VERSION 5.8 ;
BUSBITCHARS "[]" ;
DIVIDERCHAR "/" ;
UNITS
    DATABASE MICRONS 1000 ;
END UNITS

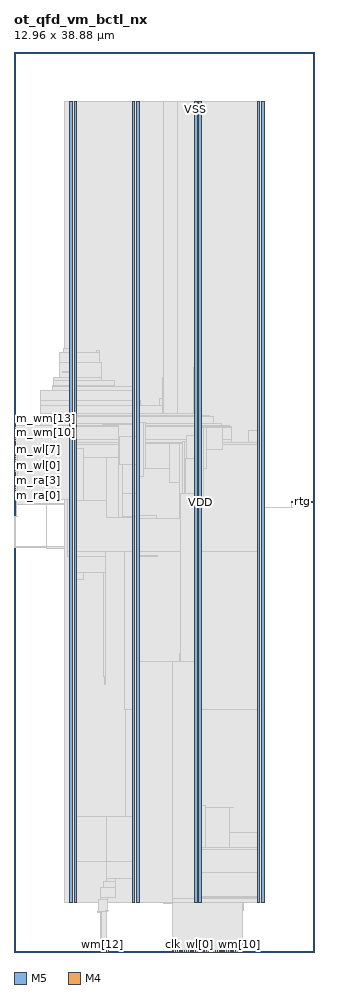
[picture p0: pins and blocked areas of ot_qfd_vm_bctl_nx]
MACRO ot_qfd_vm_bctl_nx
  FOREIGN ot_qfd_vm_bctl_nx 0 0 ;
  CLASS BLOCK ;
  SIZE 12.96 BY 38.88 ;
  PIN clk
    DIRECTION INPUT ;
    USE SIGNAL ;
    PORT
      LAYER M5 ;
        RECT  6.864 0 6.888 0.084 ;
    END
  END clk
  PIN m_ra[0]
    DIRECTION OUTPUT ;
    USE SIGNAL ;
    PORT
      LAYER M4 ;
        RECT  0 19.728 0.084 19.752 ;
    END
  END m_ra[0]
  PIN m_ra[1]
    DIRECTION OUTPUT ;
    USE SIGNAL ;
    PORT
      LAYER M4 ;
        RECT  0 19.824 0.084 19.848 ;
    END
  END m_ra[1]
  PIN m_ra[2]
    DIRECTION OUTPUT ;
    USE SIGNAL ;
    PORT
      LAYER M4 ;
        RECT  0 19.92 0.084 19.944 ;
    END
  END m_ra[2]
  PIN m_ra[3]
    DIRECTION OUTPUT ;
    USE SIGNAL ;
    PORT
      LAYER M4 ;
        RECT  0 20.016 0.084 20.04 ;
    END
  END m_ra[3]
  PIN m_ra[4]
    DIRECTION OUTPUT ;
    USE SIGNAL ;
    PORT
      LAYER M4 ;
        RECT  0 20.112 0.084 20.136 ;
    END
  END m_ra[4]
  PIN m_ra[5]
    DIRECTION OUTPUT ;
    USE SIGNAL ;
    PORT
      LAYER M4 ;
        RECT  0 20.208 0.084 20.232 ;
    END
  END m_ra[5]
  PIN m_ra[6]
    DIRECTION OUTPUT ;
    USE SIGNAL ;
    PORT
      LAYER M4 ;
        RECT  0 20.304 0.084 20.328 ;
    END
  END m_ra[6]
  PIN m_ra[7]
    DIRECTION OUTPUT ;
    USE SIGNAL ;
    PORT
      LAYER M4 ;
        RECT  0 20.4 0.084 20.424 ;
    END
  END m_ra[7]
  PIN m_re
    DIRECTION OUTPUT ;
    USE SIGNAL ;
    PORT
      LAYER M4 ;
        RECT  0 20.496 0.084 20.52 ;
    END
  END m_re
  PIN m_we
    DIRECTION OUTPUT ;
    USE SIGNAL ;
    PORT
      LAYER M4 ;
        RECT  0 20.592 0.084 20.616 ;
    END
  END m_we
  PIN m_wl[0]
    DIRECTION OUTPUT ;
    USE SIGNAL ;
    PORT
      LAYER M4 ;
        RECT  0 20.688 0.084 20.712 ;
    END
  END m_wl[0]
  PIN m_wl[1]
    DIRECTION OUTPUT ;
    USE SIGNAL ;
    PORT
      LAYER M4 ;
        RECT  0 20.784 0.084 20.808 ;
    END
  END m_wl[1]
  PIN m_wl[2]
    DIRECTION OUTPUT ;
    USE SIGNAL ;
    PORT
      LAYER M4 ;
        RECT  0 20.88 0.084 20.904 ;
    END
  END m_wl[2]
  PIN m_wl[3]
    DIRECTION OUTPUT ;
    USE SIGNAL ;
    PORT
      LAYER M4 ;
        RECT  0 20.976 0.084 21 ;
    END
  END m_wl[3]
  PIN m_wl[4]
    DIRECTION OUTPUT ;
    USE SIGNAL ;
    PORT
      LAYER M4 ;
        RECT  0 21.072 0.084 21.096 ;
    END
  END m_wl[4]
  PIN m_wl[5]
    DIRECTION OUTPUT ;
    USE SIGNAL ;
    PORT
      LAYER M4 ;
        RECT  0 21.168 0.084 21.192 ;
    END
  END m_wl[5]
  PIN m_wl[6]
    DIRECTION OUTPUT ;
    USE SIGNAL ;
    PORT
      LAYER M4 ;
        RECT  0 21.264 0.084 21.288 ;
    END
  END m_wl[6]
  PIN m_wl[7]
    DIRECTION OUTPUT ;
    USE SIGNAL ;
    PORT
      LAYER M4 ;
        RECT  0 21.36 0.084 21.384 ;
    END
  END m_wl[7]
  PIN m_wm[0]
    DIRECTION OUTPUT ;
    USE SIGNAL ;
    PORT
      LAYER M4 ;
        RECT  0 21.456 0.084 21.48 ;
    END
  END m_wm[0]
  PIN m_wm[10]
    DIRECTION OUTPUT ;
    USE SIGNAL ;
    PORT
      LAYER M4 ;
        RECT  0 22.416 0.084 22.44 ;
    END
  END m_wm[10]
  PIN m_wm[11]
    DIRECTION OUTPUT ;
    USE SIGNAL ;
    PORT
      LAYER M4 ;
        RECT  0 22.512 0.084 22.536 ;
    END
  END m_wm[11]
  PIN m_wm[12]
    DIRECTION OUTPUT ;
    USE SIGNAL ;
    PORT
      LAYER M4 ;
        RECT  0 22.608 0.084 22.632 ;
    END
  END m_wm[12]
  PIN m_wm[13]
    DIRECTION OUTPUT ;
    USE SIGNAL ;
    PORT
      LAYER M4 ;
        RECT  0 22.704 0.084 22.728 ;
    END
  END m_wm[13]
  PIN m_wm[14]
    DIRECTION OUTPUT ;
    USE SIGNAL ;
    PORT
      LAYER M4 ;
        RECT  0 19.536 0.084 19.56 ;
    END
  END m_wm[14]
  PIN m_wm[15]
    DIRECTION OUTPUT ;
    USE SIGNAL ;
    PORT
      LAYER M4 ;
        RECT  0 19.632 0.084 19.656 ;
    END
  END m_wm[15]
  PIN m_wm[1]
    DIRECTION OUTPUT ;
    USE SIGNAL ;
    PORT
      LAYER M4 ;
        RECT  0 21.552 0.084 21.576 ;
    END
  END m_wm[1]
  PIN m_wm[2]
    DIRECTION OUTPUT ;
    USE SIGNAL ;
    PORT
      LAYER M4 ;
        RECT  0 21.648 0.084 21.672 ;
    END
  END m_wm[2]
  PIN m_wm[3]
    DIRECTION OUTPUT ;
    USE SIGNAL ;
    PORT
      LAYER M4 ;
        RECT  0 21.744 0.084 21.768 ;
    END
  END m_wm[3]
  PIN m_wm[4]
    DIRECTION OUTPUT ;
    USE SIGNAL ;
    PORT
      LAYER M4 ;
        RECT  0 21.84 0.084 21.864 ;
    END
  END m_wm[4]
  PIN m_wm[5]
    DIRECTION OUTPUT ;
    USE SIGNAL ;
    PORT
      LAYER M4 ;
        RECT  0 21.936 0.084 21.96 ;
    END
  END m_wm[5]
  PIN m_wm[6]
    DIRECTION OUTPUT ;
    USE SIGNAL ;
    PORT
      LAYER M4 ;
        RECT  0 22.032 0.084 22.056 ;
    END
  END m_wm[6]
  PIN m_wm[7]
    DIRECTION OUTPUT ;
    USE SIGNAL ;
    PORT
      LAYER M4 ;
        RECT  0 22.128 0.084 22.152 ;
    END
  END m_wm[7]
  PIN m_wm[8]
    DIRECTION OUTPUT ;
    USE SIGNAL ;
    PORT
      LAYER M4 ;
        RECT  0 22.224 0.084 22.248 ;
    END
  END m_wm[8]
  PIN m_wm[9]
    DIRECTION OUTPUT ;
    USE SIGNAL ;
    PORT
      LAYER M4 ;
        RECT  0 22.32 0.084 22.344 ;
    END
  END m_wm[9]
  PIN ra[0]
    DIRECTION INPUT ;
    USE SIGNAL ;
    PORT
      LAYER M5 ;
        RECT  6.96 0 6.984 0.084 ;
    END
  END ra[0]
  PIN ra[1]
    DIRECTION INPUT ;
    USE SIGNAL ;
    PORT
      LAYER M5 ;
        RECT  7.056 0 7.08 0.084 ;
    END
  END ra[1]
  PIN ra[2]
    DIRECTION INPUT ;
    USE SIGNAL ;
    PORT
      LAYER M5 ;
        RECT  7.152 0 7.176 0.084 ;
    END
  END ra[2]
  PIN ra[3]
    DIRECTION INPUT ;
    USE SIGNAL ;
    PORT
      LAYER M5 ;
        RECT  7.248 0 7.272 0.084 ;
    END
  END ra[3]
  PIN ra[4]
    DIRECTION INPUT ;
    USE SIGNAL ;
    PORT
      LAYER M5 ;
        RECT  7.344 0 7.368 0.084 ;
    END
  END ra[4]
  PIN ra[5]
    DIRECTION INPUT ;
    USE SIGNAL ;
    PORT
      LAYER M5 ;
        RECT  7.44 0 7.464 0.084 ;
    END
  END ra[5]
  PIN ra[6]
    DIRECTION INPUT ;
    USE SIGNAL ;
    PORT
      LAYER M5 ;
        RECT  7.536 0 7.56 0.084 ;
    END
  END ra[6]
  PIN ra[7]
    DIRECTION INPUT ;
    USE SIGNAL ;
    PORT
      LAYER M5 ;
        RECT  7.632 0 7.656 0.084 ;
    END
  END ra[7]
  PIN re
    DIRECTION INPUT ;
    USE SIGNAL ;
    PORT
      LAYER M5 ;
        RECT  7.728 0 7.752 0.084 ;
    END
  END re
  PIN rst_n
    DIRECTION INPUT ;
    USE SIGNAL ;
    PORT
      LAYER M5 ;
        RECT  7.824 0 7.848 0.084 ;
    END
  END rst_n
  PIN rtg
    DIRECTION OUTPUT ;
    USE SIGNAL ;
    PORT
      LAYER M4 ;
        RECT  12.876 19.44 12.96 19.464 ;
    END
    PORT
      LAYER M4 ;
        RECT  11.977 19.44 12.924 19.464 ;
    END
  END rtg
  PIN we
    DIRECTION INPUT ;
    USE SIGNAL ;
    PORT
      LAYER M5 ;
        RECT  7.92 0 7.944 0.084 ;
    END
  END we
  PIN wl[0]
    DIRECTION INPUT ;
    USE SIGNAL ;
    PORT
      LAYER M5 ;
        RECT  8.016 0 8.04 0.084 ;
    END
  END wl[0]
  PIN wl[1]
    DIRECTION INPUT ;
    USE SIGNAL ;
    PORT
      LAYER M5 ;
        RECT  8.112 0 8.136 0.084 ;
    END
  END wl[1]
  PIN wl[2]
    DIRECTION INPUT ;
    USE SIGNAL ;
    PORT
      LAYER M5 ;
        RECT  8.208 0 8.232 0.084 ;
    END
  END wl[2]
  PIN wl[3]
    DIRECTION INPUT ;
    USE SIGNAL ;
    PORT
      LAYER M5 ;
        RECT  8.304 0 8.328 0.084 ;
    END
  END wl[3]
  PIN wl[4]
    DIRECTION INPUT ;
    USE SIGNAL ;
    PORT
      LAYER M5 ;
        RECT  8.4 0 8.424 0.084 ;
    END
  END wl[4]
  PIN wl[5]
    DIRECTION INPUT ;
    USE SIGNAL ;
    PORT
      LAYER M5 ;
        RECT  8.496 0 8.52 0.084 ;
    END
  END wl[5]
  PIN wl[6]
    DIRECTION INPUT ;
    USE SIGNAL ;
    PORT
      LAYER M5 ;
        RECT  8.592 0 8.616 0.084 ;
    END
  END wl[6]
  PIN wl[7]
    DIRECTION INPUT ;
    USE SIGNAL ;
    PORT
      LAYER M5 ;
        RECT  8.688 0 8.712 0.084 ;
    END
  END wl[7]
  PIN wm[0]
    DIRECTION INPUT ;
    USE SIGNAL ;
    PORT
      LAYER M5 ;
        RECT  8.784 0 8.808 0.084 ;
    END
  END wm[0]
  PIN wm[10]
    DIRECTION INPUT ;
    USE SIGNAL ;
    PORT
      LAYER M5 ;
        RECT  9.744 0 9.768 0.084 ;
    END
  END wm[10]
  PIN wm[11]
    DIRECTION INPUT ;
    USE SIGNAL ;
    PORT
      LAYER M5 ;
        RECT  9.84 0 9.864 0.084 ;
    END
  END wm[11]
  PIN wm[12]
    DIRECTION INPUT ;
    USE SIGNAL ;
    PORT
      LAYER M5 ;
        RECT  3.792 0 3.816 0.084 ;
    END
  END wm[12]
  PIN wm[13]
    DIRECTION INPUT ;
    USE SIGNAL ;
    PORT
      LAYER M5 ;
        RECT  3.888 0 3.912 0.084 ;
    END
  END wm[13]
  PIN wm[14]
    DIRECTION INPUT ;
    USE SIGNAL ;
    PORT
      LAYER M5 ;
        RECT  3.984 0 4.008 0.084 ;
    END
  END wm[14]
  PIN wm[15]
    DIRECTION INPUT ;
    USE SIGNAL ;
    PORT
      LAYER M5 ;
        RECT  4.08 0 4.104 0.084 ;
    END
  END wm[15]
  PIN wm[1]
    DIRECTION INPUT ;
    USE SIGNAL ;
    PORT
      LAYER M5 ;
        RECT  8.88 0 8.904 0.084 ;
    END
  END wm[1]
  PIN wm[2]
    DIRECTION INPUT ;
    USE SIGNAL ;
    PORT
      LAYER M5 ;
        RECT  8.976 0 9 0.084 ;
    END
  END wm[2]
  PIN wm[3]
    DIRECTION INPUT ;
    USE SIGNAL ;
    PORT
      LAYER M5 ;
        RECT  9.072 0 9.096 0.084 ;
    END
  END wm[3]
  PIN wm[4]
    DIRECTION INPUT ;
    USE SIGNAL ;
    PORT
      LAYER M5 ;
        RECT  9.168 0 9.192 0.084 ;
    END
  END wm[4]
  PIN wm[5]
    DIRECTION INPUT ;
    USE SIGNAL ;
    PORT
      LAYER M5 ;
        RECT  9.264 0 9.288 0.084 ;
    END
  END wm[5]
  PIN wm[6]
    DIRECTION INPUT ;
    USE SIGNAL ;
    PORT
      LAYER M5 ;
        RECT  9.36 0 9.384 0.084 ;
    END
  END wm[6]
  PIN wm[7]
    DIRECTION INPUT ;
    USE SIGNAL ;
    PORT
      LAYER M5 ;
        RECT  9.456 0 9.48 0.084 ;
    END
  END wm[7]
  PIN wm[8]
    DIRECTION INPUT ;
    USE SIGNAL ;
    PORT
      LAYER M5 ;
        RECT  9.552 0 9.576 0.084 ;
    END
  END wm[8]
  PIN wm[9]
    DIRECTION INPUT ;
    USE SIGNAL ;
    PORT
      LAYER M5 ;
        RECT  9.648 0 9.672 0.084 ;
    END
  END wm[9]
  PIN VDD
    DIRECTION INOUT ;
    USE POWER ;
    PORT
      LAYER M5 ;
        RECT  10.692 2.151 10.812 36.729 ;
        RECT  7.992 2.151 8.112 36.729 ;
        RECT  5.292 2.151 5.412 36.729 ;
        RECT  2.592 2.151 2.712 36.729 ;
    END
  END VDD
  PIN VSS
    DIRECTION INOUT ;
    USE GROUND ;
    PORT
      LAYER M5 ;
        RECT  10.5 2.137 10.62 36.743 ;
        RECT  7.8 2.137 7.92 36.743 ;
        RECT  5.1 2.137 5.22 36.743 ;
        RECT  2.4 2.137 2.52 36.743 ;
    END
  END VSS
  # OT_OBS_CLOSED layer=M5 d_um=1.536 added=5
  OBS
    LAYER RVTN ;
     RECT  2.16 2.16 10.8 2.295 ;
     RECT  2.16 2.565 10.8 2.835 ;
     RECT  2.16 3.105 10.8 3.375 ;
     RECT  2.16 3.645 10.8 3.915 ;
     RECT  2.16 4.185 10.8 4.455 ;
     RECT  2.16 4.725 10.8 4.995 ;
     RECT  2.16 5.265 10.8 5.535 ;
     RECT  2.16 5.805 10.8 6.075 ;
     RECT  2.16 6.345 10.8 6.615 ;
     RECT  2.16 6.885 10.8 7.155 ;
     RECT  2.16 7.425 10.8 7.695 ;
     RECT  2.16 7.965 10.8 8.235 ;
     RECT  2.16 8.505 10.8 8.775 ;
     RECT  2.16 9.045 10.8 9.315 ;
     RECT  2.16 9.585 10.8 9.855 ;
     RECT  2.16 10.125 10.8 10.395 ;
     RECT  2.16 10.665 10.8 10.935 ;
     RECT  2.16 11.205 10.8 11.475 ;
     RECT  2.16 11.745 10.8 12.015 ;
     RECT  2.16 12.285 10.8 12.555 ;
     RECT  2.16 12.825 10.8 13.095 ;
     RECT  2.16 13.365 10.8 13.635 ;
     RECT  2.16 13.905 10.8 14.175 ;
     RECT  2.16 14.445 10.8 14.715 ;
     RECT  2.16 14.985 10.8 15.255 ;
     RECT  2.16 15.525 10.8 15.795 ;
     RECT  2.16 16.065 10.8 16.335 ;
     RECT  2.16 16.605 10.8 16.875 ;
     RECT  2.16 17.145 10.8 17.415 ;
     RECT  2.16 17.685 10.8 17.955 ;
     RECT  2.16 18.225 10.8 18.495 ;
     RECT  2.16 18.765 10.8 19.035 ;
     RECT  2.16 19.305 10.8 19.575 ;
     RECT  2.16 19.845 10.8 20.115 ;
     RECT  2.16 20.385 10.8 20.655 ;
     RECT  2.16 20.925 10.8 21.195 ;
     RECT  2.16 21.465 10.8 21.735 ;
     RECT  2.16 22.005 10.8 22.275 ;
     RECT  2.16 22.545 10.8 22.815 ;
     RECT  2.16 23.085 10.8 23.355 ;
     RECT  2.16 23.625 10.8 23.895 ;
     RECT  2.16 24.165 10.8 24.435 ;
     RECT  2.16 24.705 10.8 24.975 ;
     RECT  2.16 25.245 10.8 25.515 ;
     RECT  2.16 25.785 10.8 26.055 ;
     RECT  2.16 26.325 10.8 26.595 ;
     RECT  2.16 26.865 10.8 27.135 ;
     RECT  2.16 27.405 10.8 27.675 ;
     RECT  2.16 27.945 10.8 28.215 ;
     RECT  2.16 28.485 10.8 28.755 ;
     RECT  2.16 29.025 10.8 29.295 ;
     RECT  2.16 29.565 10.8 29.835 ;
     RECT  2.16 30.105 10.8 30.375 ;
     RECT  2.16 30.645 10.8 30.915 ;
     RECT  2.16 31.185 10.8 31.455 ;
     RECT  2.16 31.725 10.8 31.995 ;
     RECT  2.16 32.265 10.8 32.535 ;
     RECT  2.16 32.805 10.8 33.075 ;
     RECT  2.16 33.345 10.8 33.615 ;
     RECT  2.16 33.885 10.8 34.155 ;
     RECT  2.16 34.425 10.8 34.695 ;
     RECT  2.16 34.965 10.8 35.235 ;
     RECT  2.16 35.505 10.8 35.775 ;
     RECT  2.16 36.045 10.8 36.315 ;
     RECT  2.16 36.585 10.8 36.72 ;
    LAYER RVTP ;
     RECT  2.16 2.295 10.8 2.565 ;
     RECT  2.16 2.835 10.8 3.105 ;
     RECT  2.16 3.375 10.8 3.645 ;
     RECT  2.16 3.915 10.8 4.185 ;
     RECT  2.16 4.455 10.8 4.725 ;
     RECT  2.16 4.995 10.8 5.265 ;
     RECT  2.16 5.535 10.8 5.805 ;
     RECT  2.16 6.075 10.8 6.345 ;
     RECT  2.16 6.615 10.8 6.885 ;
     RECT  2.16 7.155 10.8 7.425 ;
     RECT  2.16 7.695 10.8 7.965 ;
     RECT  2.16 8.235 10.8 8.505 ;
     RECT  2.16 8.775 10.8 9.045 ;
     RECT  2.16 9.315 10.8 9.585 ;
     RECT  2.16 9.855 10.8 10.125 ;
     RECT  2.16 10.395 10.8 10.665 ;
     RECT  2.16 10.935 10.8 11.205 ;
     RECT  2.16 11.475 10.8 11.745 ;
     RECT  2.16 12.015 10.8 12.285 ;
     RECT  2.16 12.555 10.8 12.825 ;
     RECT  2.16 13.095 10.8 13.365 ;
     RECT  2.16 13.635 10.8 13.905 ;
     RECT  2.16 14.175 10.8 14.445 ;
     RECT  2.16 14.715 10.8 14.985 ;
     RECT  2.16 15.255 10.8 15.525 ;
     RECT  2.16 15.795 10.8 16.065 ;
     RECT  2.16 16.335 10.8 16.605 ;
     RECT  2.16 16.875 10.8 17.145 ;
     RECT  2.16 17.415 10.8 17.685 ;
     RECT  2.16 17.955 10.8 18.225 ;
     RECT  2.16 18.495 10.8 18.765 ;
     RECT  2.16 19.035 10.8 19.305 ;
     RECT  2.16 19.575 10.8 19.845 ;
     RECT  2.16 20.115 10.8 20.385 ;
     RECT  2.16 20.655 10.8 20.925 ;
     RECT  2.16 21.195 10.8 21.465 ;
     RECT  2.16 21.735 10.8 22.005 ;
     RECT  2.16 22.275 10.8 22.545 ;
     RECT  2.16 22.815 10.8 23.085 ;
     RECT  2.16 23.355 10.8 23.625 ;
     RECT  2.16 23.895 10.8 24.165 ;
     RECT  2.16 24.435 10.8 24.705 ;
     RECT  2.16 24.975 10.8 25.245 ;
     RECT  2.16 25.515 10.8 25.785 ;
     RECT  2.16 26.055 10.8 26.325 ;
     RECT  2.16 26.595 10.8 26.865 ;
     RECT  2.16 27.135 10.8 27.405 ;
     RECT  2.16 27.675 10.8 27.945 ;
     RECT  2.16 28.215 10.8 28.485 ;
     RECT  2.16 28.755 10.8 29.025 ;
     RECT  2.16 29.295 10.8 29.565 ;
     RECT  2.16 29.835 10.8 30.105 ;
     RECT  2.16 30.375 10.8 30.645 ;
     RECT  2.16 30.915 10.8 31.185 ;
     RECT  2.16 31.455 10.8 31.725 ;
     RECT  2.16 31.995 10.8 32.265 ;
     RECT  2.16 32.535 10.8 32.805 ;
     RECT  2.16 33.075 10.8 33.345 ;
     RECT  2.16 33.615 10.8 33.885 ;
     RECT  2.16 34.155 10.8 34.425 ;
     RECT  2.16 34.695 10.8 34.965 ;
     RECT  2.16 35.235 10.8 35.505 ;
     RECT  2.16 35.775 10.8 36.045 ;
     RECT  2.16 36.315 10.8 36.585 ;
    LAYER M1 ;
     RECT  2.16 2.151 10.8 36.729 ;
    LAYER M2 ;
     RECT  0.031 18.81 0.131 18.828 ;
     RECT  0.175 20.196 0.211 20.214 ;
     RECT  0.211 20.124 0.535 20.214 ;
     RECT  0.031 17.496 1.399 17.514 ;
     RECT  1.147 24.246 1.651 24.264 ;
     RECT  1.651 24.246 1.687 24.462 ;
     RECT  1.975 25.866 2.047 25.884 ;
     RECT  2.047 25.794 2.119 25.884 ;
     RECT  1.399 17.424 2.16 17.514 ;
     RECT  0.535 19.35 2.16 19.368 ;
     RECT  0.535 20.124 2.16 20.484 ;
     RECT  1.687 24.246 2.16 24.804 ;
     RECT  2.119 25.794 2.16 26.082 ;
     RECT  2.16 2.151 6.439 36.729 ;
     RECT  6.439 2.106 7.079 36.729 ;
     RECT  7.079 2.151 10.8 36.729 ;
     RECT  10.8 2.421 10.812 36.459 ;
     RECT  10.812 19.206 12.011 19.224 ;
    LAYER M3 ;
     RECT  7.056 0.571 7.434 1.147 ;
     RECT  7.056 1.147 7.614 1.675 ;
     RECT  3.744 0.091 3.762 1.723 ;
     RECT  6.912 1.675 7.614 1.723 ;
     RECT  9.144 1.147 9.162 1.723 ;
     RECT  3.636 1.723 3.942 1.771 ;
     RECT  6.912 1.723 9.81 1.771 ;
     RECT  6.912 1.771 9.882 2.101 ;
     RECT  6.444 2.101 9.882 2.143 ;
     RECT  3.636 1.771 4.05 2.255 ;
     RECT  3.744 2.255 4.05 2.371 ;
     RECT  6.444 2.143 10.605 2.371 ;
     RECT  2.415 2.143 2.505 2.413 ;
     RECT  5.115 2.143 5.205 2.413 ;
     RECT  6.408 2.371 10.605 2.413 ;
     RECT  3.744 2.371 4.374 2.795 ;
     RECT  3.852 2.795 4.374 3.029 ;
     RECT  3.996 3.029 4.374 3.181 ;
     RECT  5.115 2.413 5.397 3.181 ;
     RECT  6.408 2.413 10.797 3.451 ;
     RECT  3.996 3.181 5.397 4.379 ;
     RECT  4.824 4.379 5.397 4.423 ;
     RECT  6.372 3.451 10.797 4.423 ;
     RECT  3.924 4.495 3.942 4.541 ;
     RECT  4.824 4.423 10.797 10.471 ;
     RECT  3.924 11.551 3.942 11.911 ;
     RECT  2.415 2.413 2.697 16.105 ;
     RECT  2.415 16.105 3.006 16.411 ;
     RECT  3.852 11.911 3.942 16.411 ;
     RECT  2.415 16.411 3.942 17.077 ;
     RECT  2.304 17.077 3.942 17.311 ;
     RECT  4.788 10.471 10.797 17.311 ;
     RECT  0.036 17.491 0.054 18.805 ;
     RECT  0.036 18.805 0.126 18.833 ;
     RECT  0.108 18.833 0.126 19.345 ;
     RECT  11.988 19.201 12.006 19.469 ;
     RECT  0.108 19.345 0.558 20.237 ;
     RECT  0.18 20.237 0.558 20.621 ;
     RECT  1.404 17.419 1.422 20.813 ;
     RECT  0.18 20.621 0.234 21.403 ;
     RECT  0.144 21.403 0.234 21.581 ;
     RECT  0.324 21.643 0.342 21.773 ;
     RECT  2.304 17.311 10.797 21.931 ;
     RECT  2.232 21.931 10.797 22.001 ;
     RECT  2.232 22.001 9.378 22.027 ;
     RECT  1.152 21.883 1.17 22.123 ;
     RECT  2.196 22.027 9.378 22.123 ;
     RECT  10.116 22.001 10.797 22.541 ;
     RECT  1.152 22.123 9.378 22.685 ;
     RECT  1.152 22.685 9.306 22.739 ;
     RECT  1.152 22.739 8.946 22.811 ;
     RECT  1.152 22.811 8.622 23.117 ;
     RECT  1.152 23.117 8.442 23.189 ;
     RECT  1.152 23.189 8.097 23.279 ;
     RECT  1.152 23.279 6.426 23.621 ;
     RECT  1.152 23.621 5.454 23.819 ;
     RECT  6.264 23.621 6.426 23.891 ;
     RECT  1.152 23.819 5.397 24.269 ;
     RECT  1.656 24.269 5.397 24.431 ;
     RECT  1.656 24.431 4.338 24.467 ;
     RECT  1.692 24.467 4.338 24.701 ;
     RECT  1.692 24.701 3.762 24.809 ;
     RECT  6.408 23.891 6.426 24.809 ;
     RECT  7.776 23.279 8.097 25.241 ;
     RECT  1.98 24.809 3.762 25.475 ;
     RECT  1.98 25.475 3.69 25.889 ;
     RECT  3.564 25.889 3.69 25.979 ;
     RECT  2.124 25.889 2.697 26.087 ;
     RECT  2.415 26.087 2.697 36.467 ;
     RECT  5.115 24.431 5.397 36.467 ;
     RECT  7.815 25.241 8.097 36.467 ;
     RECT  10.515 22.541 10.797 36.467 ;
     RECT  2.415 36.467 2.505 36.737 ;
     RECT  5.115 36.467 5.205 36.737 ;
     RECT  7.815 36.467 7.905 36.737 ;
     RECT  10.515 36.467 10.605 36.737 ;
    LAYER M4 ;
     RECT  0.06 19.536 2.408 22.728 ;
     RECT  2.077 25.056 2.408 25.08 ;
     RECT  2.408 2.148 2.512 36.732 ;
     RECT  2.512 2.418 2.704 36.462 ;
     RECT  2.704 19.488 2.981 21.768 ;
     RECT  3.913 4.512 3.941 4.536 ;
     RECT  3.625 1.728 3.963 1.752 ;
     RECT  3.963 1.728 3.964 1.8 ;
     RECT  2.981 19.488 3.985 21.384 ;
     RECT  3.941 3.936 4.019 4.536 ;
     RECT  3.964 1.776 4.061 1.8 ;
     RECT  3.733 0.096 4.115 0.12 ;
     RECT  3.985 18.768 4.525 21.384 ;
     RECT  3.841 22.752 4.525 22.776 ;
     RECT  4.019 3.936 5.108 3.96 ;
     RECT  3.973 5.808 5.108 5.832 ;
     RECT  4.525 18.768 5.108 22.776 ;
     RECT  5.108 2.148 5.212 36.732 ;
     RECT  5.212 2.418 5.404 36.462 ;
     RECT  5.404 20.544 5.609 22.872 ;
     RECT  5.609 20.88 5.681 22.872 ;
     RECT  5.404 18.72 6.149 18.84 ;
     RECT  5.404 17.088 6.185 17.112 ;
     RECT  5.681 20.88 6.721 21.96 ;
     RECT  5.404 5.712 7.081 5.832 ;
     RECT  7.045 0.576 7.117 0.6 ;
     RECT  6.853 12.528 7.148 12.552 ;
     RECT  6.149 18.72 7.153 18.744 ;
     RECT  6.721 20.304 7.153 21.96 ;
     RECT  6.901 1.68 7.189 1.704 ;
     RECT  7.153 18.72 7.261 21.96 ;
     RECT  7.261 18.72 7.381 22.056 ;
     RECT  7.381 18 7.441 22.056 ;
     RECT  7.189 1.68 7.477 1.752 ;
     RECT  7.117 0.576 7.489 0.648 ;
     RECT  7.477 1.68 7.585 2.28 ;
     RECT  6.929 3.936 7.657 3.96 ;
     RECT  7.585 1.152 7.669 2.28 ;
     RECT  7.669 1.728 7.808 2.28 ;
     RECT  7.657 3.936 7.808 4.68 ;
     RECT  7.081 5.712 7.808 6.312 ;
     RECT  7.148 12.528 7.808 12.888 ;
     RECT  7.441 18 7.808 22.296 ;
     RECT  7.669 0.144 7.859 0.168 ;
     RECT  7.808 1.728 7.912 36.732 ;
     RECT  7.912 1.728 8.104 36.462 ;
     RECT  8.104 19.536 8.165 22.68 ;
     RECT  8.104 4.512 8.273 6.312 ;
     RECT  8.165 19.536 8.309 19.56 ;
     RECT  8.165 20.88 8.309 22.68 ;
     RECT  8.309 21.696 8.993 22.68 ;
     RECT  8.104 1.728 9.133 2.28 ;
     RECT  8.273 4.512 9.317 6.264 ;
     RECT  8.993 22.656 9.389 22.68 ;
     RECT  9.133 1.152 9.395 2.28 ;
     RECT  9.317 6.24 9.497 6.264 ;
     RECT  9.395 1.728 9.821 2.28 ;
     RECT  9.821 1.776 9.893 2.28 ;
     RECT  9.893 2.148 10.508 2.28 ;
     RECT  9.317 4.512 10.508 5.16 ;
     RECT  10.508 2.148 10.612 36.732 ;
     RECT  10.612 2.418 10.804 36.462 ;
    LAYER M5 ;
     RECT  3.792 0.016 4.104 0.131 ;
     RECT  3.792 0.131 4.008 1.763 ;
     RECT  3.984 1.763 4.008 1.811 ;
     RECT  6.864 0.016 9.864 2.137 ;
     RECT  2.4 2.137 2.52 2.151 ;
     RECT  5.1 2.137 5.22 2.151 ;
     RECT  6.864 2.137 10.62 2.151 ;
     RECT  6.864 2.151 10.812 2.291 ;
     RECT  3.984 3.925 4.008 5.843 ;
     RECT  6.864 2.291 8.112 12.563 ;
     RECT  5.1 2.151 5.412 18.805 ;
     RECT  4.704 18.805 5.412 19.811 ;
     RECT  7.2 12.563 8.112 19.811 ;
     RECT  0.144 19.621 0.168 20.339 ;
     RECT  5.1 19.811 5.412 21.061 ;
     RECT  7.392 19.811 8.112 21.299 ;
     RECT  0.144 21.733 0.168 21.923 ;
     RECT  4.56 21.061 5.412 22.259 ;
     RECT  2.4 2.151 2.712 36.729 ;
     RECT  5.1 22.259 5.412 36.729 ;
     RECT  7.8 21.299 8.112 36.729 ;
     RECT  10.5 2.291 10.812 36.729 ;
     RECT  2.4 36.729 2.52 36.743 ;
     RECT  5.1 36.729 5.22 36.743 ;
     RECT  7.8 36.729 7.92 36.743 ;
     RECT  10.5 36.729 10.62 36.743 ;
     RECT  5.412 2.151 6.864 12.563 ;
     RECT  2.712 3.925 3.984 5.843 ;
     RECT  4.008 3.925 5.1 5.843 ;
     RECT  4.704 19.811 5.1 21.061 ;
     RECT  0.144 20.339 0.168 21.733 ;
  END
END ot_qfd_vm_bctl_nx
END LIBRARY
